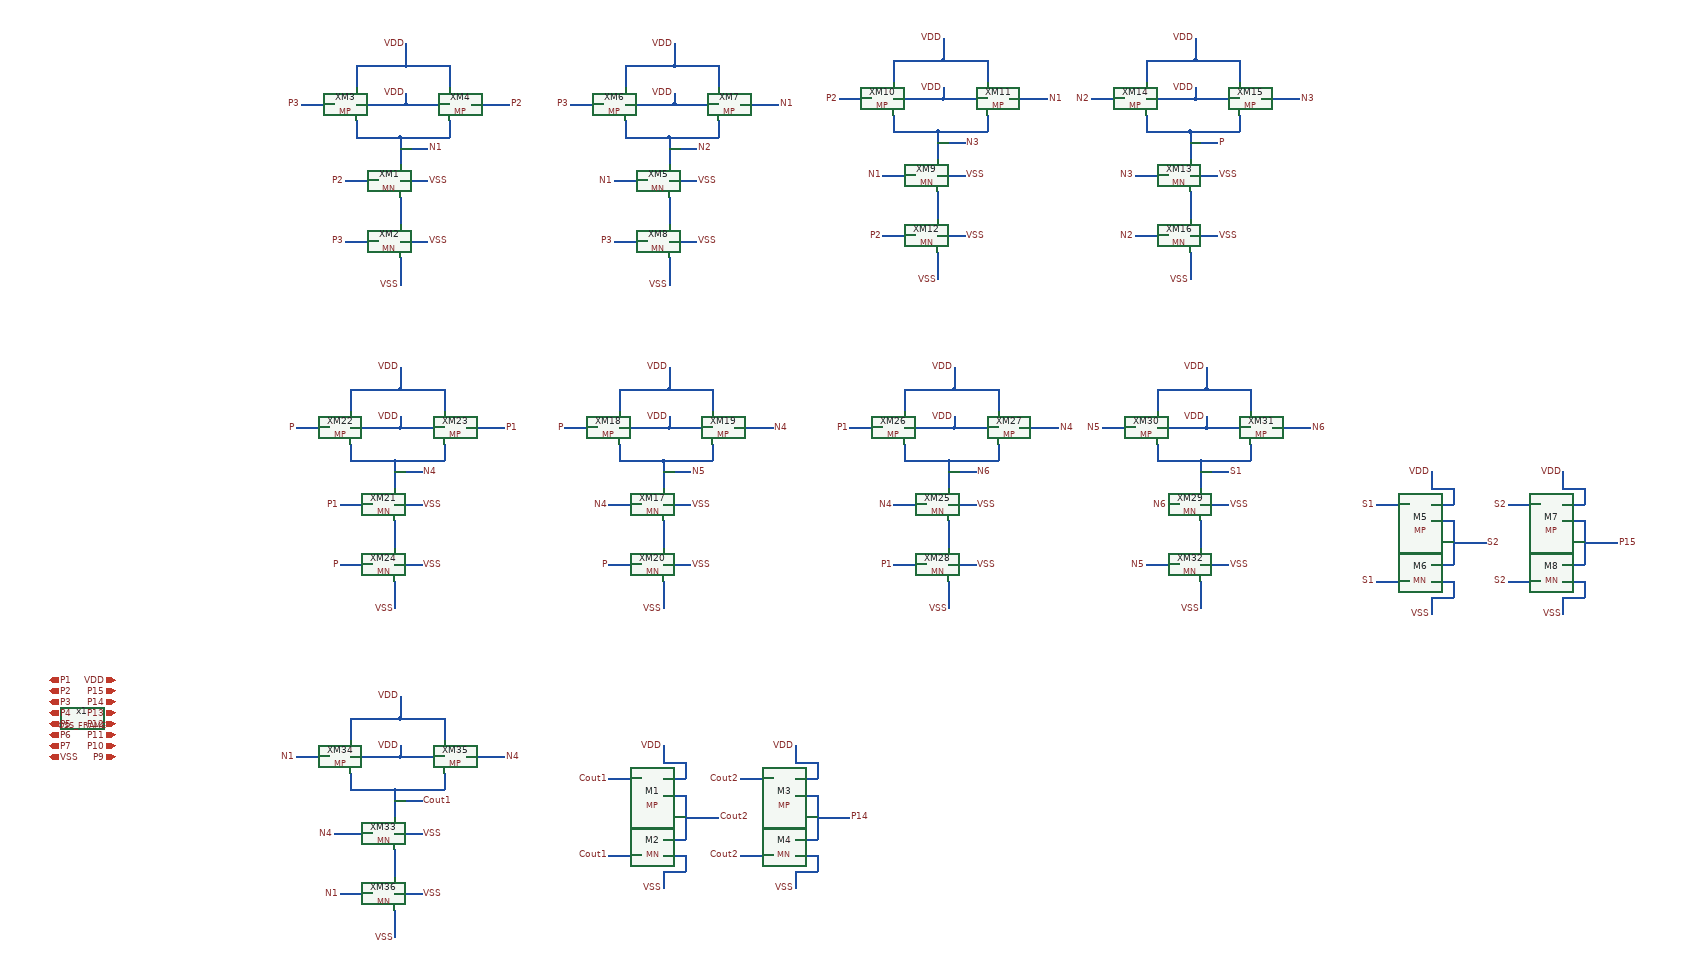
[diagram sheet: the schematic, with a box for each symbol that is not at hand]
v {xschem version=3.4.8RC file_version=1.3}
G {}
K {}
V {}
S {}
F {}
E {}
N 830 -1630 900 -1630 {lab=P2}
N 520 -1630 580 -1630 {lab=P3}
N 710 -1740 710 -1700 {lab=VDD}
N 710 -1700 790 -1700 {lab=VDD}
N 790 -1700 790 -1660 {lab=VDD}
N 620 -1700 710 -1700 {lab=VDD}
N 620 -1700 620 -1660 {lab=VDD}
N 790 -1600 790 -1570 {lab=N1}
N 700 -1570 790 -1570 {lab=N1}
N 700 -1570 700 -1520 {lab=N1}
N 620 -1600 620 -1570 {lab=N1}
N 620 -1570 700 -1570 {lab=N1}
N 700 -1550 750 -1550 {lab=N1}
N 600 -1490 660 -1490 {lab=P2}
N 600 -1380 660 -1380 {lab=P3}
N 700 -1460 700 -1440 {lab=#net1}
N 700 -1440 700 -1410 {lab=#net1}
N 700 -1350 700 -1300 {lab=VSS}
N 700 -1380 750 -1380 {lab=VSS}
N 700 -1490 750 -1490 {lab=VSS}
N 620 -1630 710 -1630 {lab=VDD}
N 710 -1650 710 -1630 {lab=VDD}
N 710 -1630 790 -1630 {lab=VDD}
N 1320 -1630 1390 -1630 {lab=N1}
N 1010 -1630 1070 -1630 {lab=P3}
N 1200 -1740 1200 -1700 {lab=VDD}
N 1200 -1700 1280 -1700 {lab=VDD}
N 1280 -1700 1280 -1660 {lab=VDD}
N 1110 -1700 1200 -1700 {lab=VDD}
N 1110 -1700 1110 -1660 {lab=VDD}
N 1280 -1600 1280 -1570 {lab=N2}
N 1190 -1570 1280 -1570 {lab=N2}
N 1190 -1570 1190 -1520 {lab=N2}
N 1110 -1600 1110 -1570 {lab=N2}
N 1110 -1570 1190 -1570 {lab=N2}
N 1190 -1550 1240 -1550 {lab=N2}
N 1090 -1490 1150 -1490 {lab=N1}
N 1090 -1380 1150 -1380 {lab=P3}
N 1190 -1460 1190 -1440 {lab=#net2}
N 1190 -1440 1190 -1410 {lab=#net2}
N 1190 -1350 1190 -1300 {lab=VSS}
N 1190 -1380 1240 -1380 {lab=VSS}
N 1190 -1490 1240 -1490 {lab=VSS}
N 1110 -1630 1200 -1630 {lab=VDD}
N 1200 -1650 1200 -1630 {lab=VDD}
N 1200 -1630 1280 -1630 {lab=VDD}
N 1810 -1640 1880 -1640 {lab=N1}
N 1500 -1640 1560 -1640 {lab=P2}
N 1690 -1750 1690 -1710 {lab=VDD}
N 1690 -1710 1770 -1710 {lab=VDD}
N 1770 -1710 1770 -1670 {lab=VDD}
N 1600 -1710 1690 -1710 {lab=VDD}
N 1600 -1710 1600 -1670 {lab=VDD}
N 1770 -1610 1770 -1580 {lab=N3}
N 1680 -1580 1770 -1580 {lab=N3}
N 1680 -1580 1680 -1530 {lab=N3}
N 1600 -1610 1600 -1580 {lab=N3}
N 1600 -1580 1680 -1580 {lab=N3}
N 1680 -1560 1730 -1560 {lab=N3}
N 1580 -1500 1640 -1500 {lab=N1}
N 1580 -1390 1640 -1390 {lab=P2}
N 1680 -1470 1680 -1450 {lab=#net3}
N 1680 -1450 1680 -1420 {lab=#net3}
N 1680 -1360 1680 -1310 {lab=VSS}
N 1680 -1390 1730 -1390 {lab=VSS}
N 1680 -1500 1730 -1500 {lab=VSS}
N 1600 -1640 1690 -1640 {lab=VDD}
N 1690 -1660 1690 -1640 {lab=VDD}
N 1690 -1640 1770 -1640 {lab=VDD}
N 2270 -1640 2340 -1640 {lab=N3}
N 1960 -1640 2020 -1640 {lab=N2}
N 2150 -1750 2150 -1710 {lab=VDD}
N 2150 -1710 2230 -1710 {lab=VDD}
N 2230 -1710 2230 -1670 {lab=VDD}
N 2060 -1710 2150 -1710 {lab=VDD}
N 2060 -1710 2060 -1670 {lab=VDD}
N 2230 -1610 2230 -1580 {lab=P}
N 2140 -1580 2230 -1580 {lab=P}
N 2140 -1580 2140 -1530 {lab=P}
N 2060 -1610 2060 -1580 {lab=P}
N 2060 -1580 2140 -1580 {lab=P}
N 2140 -1560 2190 -1560 {lab=P}
N 2040 -1500 2100 -1500 {lab=N3}
N 2040 -1390 2100 -1390 {lab=N2}
N 2140 -1470 2140 -1450 {lab=#net4}
N 2140 -1450 2140 -1420 {lab=#net4}
N 2140 -1360 2140 -1310 {lab=VSS}
N 2140 -1390 2190 -1390 {lab=VSS}
N 2140 -1500 2190 -1500 {lab=VSS}
N 2060 -1640 2150 -1640 {lab=VDD}
N 2150 -1660 2150 -1640 {lab=VDD}
N 2150 -1640 2230 -1640 {lab=VDD}
N 1310 -1040 1380 -1040 {lab=N4}
N 1000 -1040 1060 -1040 {lab=P}
N 1190 -1150 1190 -1110 {lab=VDD}
N 1190 -1110 1270 -1110 {lab=VDD}
N 1270 -1110 1270 -1070 {lab=VDD}
N 1100 -1110 1190 -1110 {lab=VDD}
N 1100 -1110 1100 -1070 {lab=VDD}
N 1270 -1010 1270 -980 {lab=N5}
N 1180 -980 1270 -980 {lab=N5}
N 1180 -980 1180 -930 {lab=N5}
N 1100 -1010 1100 -980 {lab=N5}
N 1100 -980 1180 -980 {lab=N5}
N 1180 -960 1230 -960 {lab=N5}
N 1080 -900 1140 -900 {lab=N4}
N 1080 -790 1140 -790 {lab=P}
N 1180 -870 1180 -850 {lab=#net5}
N 1180 -850 1180 -820 {lab=#net5}
N 1180 -760 1180 -710 {lab=VSS}
N 1180 -790 1230 -790 {lab=VSS}
N 1180 -900 1230 -900 {lab=VSS}
N 1100 -1040 1190 -1040 {lab=VDD}
N 1190 -1060 1190 -1040 {lab=VDD}
N 1190 -1040 1270 -1040 {lab=VDD}
N 820 -1040 890 -1040 {lab=P1}
N 510 -1040 570 -1040 {lab=P}
N 700 -1150 700 -1110 {lab=VDD}
N 700 -1110 780 -1110 {lab=VDD}
N 780 -1110 780 -1070 {lab=VDD}
N 610 -1110 700 -1110 {lab=VDD}
N 610 -1110 610 -1070 {lab=VDD}
N 780 -1010 780 -980 {lab=N4}
N 690 -980 780 -980 {lab=N4}
N 690 -980 690 -930 {lab=N4}
N 610 -1010 610 -980 {lab=N4}
N 610 -980 690 -980 {lab=N4}
N 690 -960 740 -960 {lab=N4}
N 590 -900 650 -900 {lab=P1}
N 590 -790 650 -790 {lab=P}
N 690 -870 690 -850 {lab=#net6}
N 690 -850 690 -820 {lab=#net6}
N 690 -760 690 -710 {lab=VSS}
N 690 -790 740 -790 {lab=VSS}
N 690 -900 740 -900 {lab=VSS}
N 610 -1040 700 -1040 {lab=VDD}
N 700 -1060 700 -1040 {lab=VDD}
N 700 -1040 780 -1040 {lab=VDD}
N 1830 -1040 1900 -1040 {lab=N4}
N 1520 -1040 1580 -1040 {lab=P1}
N 1710 -1150 1710 -1110 {lab=VDD}
N 1710 -1110 1790 -1110 {lab=VDD}
N 1790 -1110 1790 -1070 {lab=VDD}
N 1620 -1110 1710 -1110 {lab=VDD}
N 1620 -1110 1620 -1070 {lab=VDD}
N 1790 -1010 1790 -980 {lab=N6}
N 1700 -980 1790 -980 {lab=N6}
N 1700 -980 1700 -930 {lab=N6}
N 1620 -1010 1620 -980 {lab=N6}
N 1620 -980 1700 -980 {lab=N6}
N 1700 -960 1750 -960 {lab=N6}
N 1600 -900 1660 -900 {lab=N4}
N 1600 -790 1660 -790 {lab=P1}
N 1700 -870 1700 -850 {lab=#net7}
N 1700 -850 1700 -820 {lab=#net7}
N 1700 -760 1700 -710 {lab=VSS}
N 1700 -790 1750 -790 {lab=VSS}
N 1700 -900 1750 -900 {lab=VSS}
N 1620 -1040 1710 -1040 {lab=VDD}
N 1710 -1060 1710 -1040 {lab=VDD}
N 1710 -1040 1790 -1040 {lab=VDD}
N 2290 -1040 2360 -1040 {lab=N6}
N 1980 -1040 2040 -1040 {lab=N5}
N 2170 -1150 2170 -1110 {lab=VDD}
N 2170 -1110 2250 -1110 {lab=VDD}
N 2250 -1110 2250 -1070 {lab=VDD}
N 2080 -1110 2170 -1110 {lab=VDD}
N 2080 -1110 2080 -1070 {lab=VDD}
N 2250 -1010 2250 -980 {lab=S1}
N 2160 -980 2250 -980 {lab=S1}
N 2160 -980 2160 -930 {lab=S1}
N 2080 -1010 2080 -980 {lab=S1}
N 2080 -980 2160 -980 {lab=S1}
N 2160 -960 2210 -960 {lab=S1}
N 2060 -790 2120 -790 {lab=N5}
N 2160 -870 2160 -850 {lab=#net8}
N 2160 -850 2160 -820 {lab=#net8}
N 2160 -760 2160 -710 {lab=VSS}
N 2160 -790 2210 -790 {lab=VSS}
N 2160 -900 2210 -900 {lab=VSS}
N 2080 -1040 2170 -1040 {lab=VDD}
N 2170 -1060 2170 -1040 {lab=VDD}
N 2170 -1040 2250 -1040 {lab=VDD}
N 820 -440 890 -440 {lab=N4}
N 510 -440 570 -440 {lab=N1}
N 700 -550 700 -510 {lab=VDD}
N 700 -510 780 -510 {lab=VDD}
N 780 -510 780 -470 {lab=VDD}
N 610 -510 700 -510 {lab=VDD}
N 610 -510 610 -470 {lab=VDD}
N 780 -410 780 -380 {lab=Cout}
N 690 -380 780 -380 {lab=Cout}
N 690 -380 690 -330 {lab=Cout}
N 610 -410 610 -380 {lab=Cout}
N 610 -380 690 -380 {lab=Cout}
N 690 -360 740 -360 {lab=Cout}
N 590 -190 650 -190 {lab=N1}
N 690 -270 690 -250 {lab=#net9}
N 690 -250 690 -220 {lab=#net9}
N 690 -160 690 -110 {lab=VSS}
N 690 -190 740 -190 {lab=VSS}
N 690 -300 740 -300 {lab=VSS}
N 610 -440 700 -440 {lab=VDD}
N 700 -460 700 -440 {lab=VDD}
N 700 -440 780 -440 {lab=VDD}
N 580 -300 650 -300 {lab=N4}
N 2100 -900 2120 -900 {lab=N6}
N 1080 -400 1140 -400 {lab=Cout1}
N 1080 -260 1140 -260 {lab=Cout1}
N 1180 -370 1220 -370 {lab=Cout2}
N 1180 -290 1220 -290 {lab=Cout2}
N 1220 -370 1220 -290 {lab=Cout2}
N 1220 -330 1280 -330 {lab=Cout2}
N 1180 -460 1180 -430 {lab=VDD}
N 1180 -430 1220 -430 {lab=VDD}
N 1220 -430 1220 -400 {lab=VDD}
N 1180 -400 1220 -400 {lab=VDD}
N 1180 -230 1180 -200 {lab=VSS}
N 1180 -260 1220 -260 {lab=VSS}
N 1220 -260 1220 -230 {lab=VSS}
N 1180 -230 1220 -230 {lab=VSS}
N 1320 -400 1380 -400 {lab=Cout2}
N 1320 -260 1380 -260 {lab=Cout2}
N 1420 -370 1460 -370 {lab=P14}
N 1420 -290 1460 -290 {lab=P14}
N 1460 -370 1460 -290 {lab=P14}
N 1460 -330 1520 -330 {lab=P14}
N 1420 -460 1420 -430 {lab=VDD}
N 1420 -430 1460 -430 {lab=VDD}
N 1460 -430 1460 -400 {lab=VDD}
N 1420 -400 1460 -400 {lab=VDD}
N 1420 -230 1420 -200 {lab=VSS}
N 1420 -260 1460 -260 {lab=VSS}
N 1460 -260 1460 -230 {lab=VSS}
N 1420 -230 1460 -230 {lab=VSS}
N 2480 -900 2540 -900 {lab=S1}
N 2480 -760 2540 -760 {lab=S1}
N 2580 -870 2620 -870 {lab=S2}
N 2580 -790 2620 -790 {lab=S2}
N 2620 -870 2620 -790 {lab=S2}
N 2620 -830 2680 -830 {lab=S2}
N 2580 -960 2580 -930 {lab=VDD}
N 2580 -930 2620 -930 {lab=VDD}
N 2620 -930 2620 -900 {lab=VDD}
N 2580 -900 2620 -900 {lab=VDD}
N 2580 -730 2580 -700 {lab=VSS}
N 2580 -760 2620 -760 {lab=VSS}
N 2620 -760 2620 -730 {lab=VSS}
N 2580 -730 2620 -730 {lab=VSS}
N 2720 -900 2780 -900 {lab=S2}
N 2720 -760 2780 -760 {lab=S2}
N 2820 -870 2860 -870 {lab=P15}
N 2820 -790 2860 -790 {lab=P15}
N 2860 -870 2860 -790 {lab=P15}
N 2860 -830 2920 -830 {lab=P15}
N 2820 -960 2820 -930 {lab=VDD}
N 2820 -930 2860 -930 {lab=VDD}
N 2860 -930 2860 -900 {lab=VDD}
N 2820 -900 2860 -900 {lab=VDD}
N 2820 -730 2820 -700 {lab=VSS}
N 2820 -760 2860 -760 {lab=VSS}
N 2860 -760 2860 -730 {lab=VSS}
N 2820 -730 2860 -730 {lab=VSS}
C {devices/title.sym} 0 0 0 0 {name=l1 author="jun1okamura"}
C {OSS_FRAME.sym} 120 -510 0 0 {name=x1}
C {devices/iopin.sym} 60 -580 0 1 {name=p1 lab=P1}
C {devices/iopin.sym} 60 -560 0 1 {name=p2 lab=P2}
C {devices/iopin.sym} 60 -540 0 1 {name=p3 lab=P3}
C {devices/iopin.sym} 60 -520 0 1 {name=p4 lab=P4
}
C {devices/iopin.sym} 60 -500 0 1 {name=p5 lab=P5}
C {devices/iopin.sym} 60 -480 0 1 {name=p6 lab=P6}
C {devices/iopin.sym} 60 -460 0 1 {name=p7 lab=P7}
C {devices/iopin.sym} 60 -440 0 1 {name=p8 lab=VSS}
C {devices/iopin.sym} 180 -580 0 0 {name=p9 lab=VDD}
C {devices/iopin.sym} 180 -560 0 0 {name=p10 lab=P15}
C {devices/iopin.sym} 180 -540 0 0 {name=p11 lab=P14}
C {devices/iopin.sym} 180 -520 0 0 {name=p12 lab=P13
}
C {devices/iopin.sym} 180 -500 0 0 {name=p13 lab=P12}
C {devices/iopin.sym} 180 -480 0 0 {name=p14 lab=P11}
C {devices/iopin.sym} 180 -460 0 0 {name=p15 lab=P10}
C {devices/iopin.sym} 180 -440 0 0 {name=p16 lab=P9}
C {devices/lab_pin.sym} 520 -1630 0 0 {name=p17 sig_type=std_logic lab=P3}
C {devices/lab_pin.sym} 750 -1550 0 1 {name=p18 sig_type=std_logic lab=N1}
C {devices/lab_pin.sym} 900 -1630 2 0 {name=p19 sig_type=std_logic lab=P2}
C {TR-1umLIB/MN.sym} 660 -1490 0 0 {name=XM1
model=NMOS
w=3.4u
l=1u
m=1
spiceprefix=X
as=0
ad=0
ps=0
pd=0
nrd=0
nrs=0}
C {TR-1umLIB/MP.sym} 580 -1630 0 0 {name=XM3
model=PMOS
w=3.4u
l=1u
m=1
spiceprefix=X
as=0
ad=0
ps=0
pd=0
nrd=0
nrs=0}
C {TR-1umLIB/MP.sym} 830 -1630 0 1 {name=XM4
model=PMOS
w=3.4u
l=1u
m=1
spiceprefix=X
as=0
ad=0
ps=0
pd=0
nrd=0
nrs=0}
C {TR-1umLIB/MN.sym} 660 -1380 0 0 {name=XM2
model=NMOS
w=3.4u
l=1u
m=1
spiceprefix=X
as=0
ad=0
ps=0
pd=0
nrd=0
nrs=0}
C {devices/lab_pin.sym} 600 -1490 0 0 {name=p20 sig_type=std_logic lab=P2}
C {devices/lab_pin.sym} 600 -1380 0 0 {name=p21 sig_type=std_logic lab=P3}
C {devices/lab_pin.sym} 1010 -1630 0 0 {name=p22 sig_type=std_logic lab=P3}
C {devices/lab_pin.sym} 1240 -1550 0 1 {name=p23 sig_type=std_logic lab=N2}
C {devices/lab_pin.sym} 1390 -1630 2 0 {name=p24 sig_type=std_logic lab=N1}
C {TR-1umLIB/MN.sym} 1150 -1490 0 0 {name=XM5
model=NMOS
w=3.4u
l=1u
m=1
spiceprefix=X
as=0
ad=0
ps=0
pd=0
nrd=0
nrs=0}
C {TR-1umLIB/MP.sym} 1070 -1630 0 0 {name=XM6
model=PMOS
w=3.4u
l=1u
m=1
spiceprefix=X
as=0
ad=0
ps=0
pd=0
nrd=0
nrs=0}
C {TR-1umLIB/MP.sym} 1320 -1630 0 1 {name=XM7
model=PMOS
w=3.4u
l=1u
m=1
spiceprefix=X
as=0
ad=0
ps=0
pd=0
nrd=0
nrs=0}
C {TR-1umLIB/MN.sym} 1150 -1380 0 0 {name=XM8
model=NMOS
w=3.4u
l=1u
m=1
spiceprefix=X
as=0
ad=0
ps=0
pd=0
nrd=0
nrs=0}
C {devices/lab_pin.sym} 1090 -1490 0 0 {name=p25 sig_type=std_logic lab=N1}
C {devices/lab_pin.sym} 1090 -1380 0 0 {name=p26 sig_type=std_logic lab=P3}
C {devices/lab_pin.sym} 1500 -1640 0 0 {name=p27 sig_type=std_logic lab=P2}
C {devices/lab_pin.sym} 1730 -1560 0 1 {name=p28 sig_type=std_logic lab=N3}
C {devices/lab_pin.sym} 1880 -1640 2 0 {name=p29 sig_type=std_logic lab=N1}
C {TR-1umLIB/MN.sym} 1640 -1500 0 0 {name=XM9
model=NMOS
w=3.4u
l=1u
m=1
spiceprefix=X
as=0
ad=0
ps=0
pd=0
nrd=0
nrs=0}
C {TR-1umLIB/MP.sym} 1560 -1640 0 0 {name=XM10
model=PMOS
w=3.4u
l=1u
m=1
spiceprefix=X
as=0
ad=0
ps=0
pd=0
nrd=0
nrs=0}
C {TR-1umLIB/MP.sym} 1810 -1640 0 1 {name=XM11
model=PMOS
w=3.4u
l=1u
m=1
spiceprefix=X
as=0
ad=0
ps=0
pd=0
nrd=0
nrs=0}
C {TR-1umLIB/MN.sym} 1640 -1390 0 0 {name=XM12
model=NMOS
w=3.4u
l=1u
m=1
spiceprefix=X
as=0
ad=0
ps=0
pd=0
nrd=0
nrs=0}
C {devices/lab_pin.sym} 1580 -1500 0 0 {name=p30 sig_type=std_logic lab=N1}
C {devices/lab_pin.sym} 1580 -1390 0 0 {name=p31 sig_type=std_logic lab=P2}
C {devices/lab_pin.sym} 1960 -1640 0 0 {name=p32 sig_type=std_logic lab=N2
}
C {devices/lab_pin.sym} 2190 -1560 0 1 {name=p33 sig_type=std_logic lab=P}
C {devices/lab_pin.sym} 2340 -1640 2 0 {name=p34 sig_type=std_logic lab=N3}
C {TR-1umLIB/MN.sym} 2100 -1500 0 0 {name=XM13
model=NMOS
w=3.4u
l=1u
m=1
spiceprefix=X
as=0
ad=0
ps=0
pd=0
nrd=0
nrs=0}
C {TR-1umLIB/MP.sym} 2020 -1640 0 0 {name=XM14
model=PMOS
w=3.4u
l=1u
m=1
spiceprefix=X
as=0
ad=0
ps=0
pd=0
nrd=0
nrs=0}
C {TR-1umLIB/MP.sym} 2270 -1640 0 1 {name=XM15
model=PMOS
w=3.4u
l=1u
m=1
spiceprefix=X
as=0
ad=0
ps=0
pd=0
nrd=0
nrs=0}
C {TR-1umLIB/MN.sym} 2100 -1390 0 0 {name=XM16
model=NMOS
w=3.4u
l=1u
m=1
spiceprefix=X
as=0
ad=0
ps=0
pd=0
nrd=0
nrs=0}
C {devices/lab_pin.sym} 2040 -1500 0 0 {name=p35 sig_type=std_logic lab=N3}
C {devices/lab_pin.sym} 2040 -1390 0 0 {name=p36 sig_type=std_logic lab=N2}
C {devices/lab_pin.sym} 1000 -1040 0 0 {name=p37 sig_type=std_logic lab=P}
C {devices/lab_pin.sym} 1230 -960 0 1 {name=p38 sig_type=std_logic lab=N5}
C {devices/lab_pin.sym} 1380 -1040 2 0 {name=p39 sig_type=std_logic lab=N4}
C {TR-1umLIB/MN.sym} 1140 -900 0 0 {name=XM17
model=NMOS
w=3.4u
l=1u
m=1
spiceprefix=X
as=0
ad=0
ps=0
pd=0
nrd=0
nrs=0}
C {TR-1umLIB/MP.sym} 1060 -1040 0 0 {name=XM18
model=PMOS
w=3.4u
l=1u
m=1
spiceprefix=X
as=0
ad=0
ps=0
pd=0
nrd=0
nrs=0}
C {TR-1umLIB/MP.sym} 1310 -1040 0 1 {name=XM19
model=PMOS
w=3.4u
l=1u
m=1
spiceprefix=X
as=0
ad=0
ps=0
pd=0
nrd=0
nrs=0}
C {TR-1umLIB/MN.sym} 1140 -790 0 0 {name=XM20
model=NMOS
w=3.4u
l=1u
m=1
spiceprefix=X
as=0
ad=0
ps=0
pd=0
nrd=0
nrs=0}
C {devices/lab_pin.sym} 1080 -790 0 0 {name=p40 sig_type=std_logic lab=P}
C {devices/lab_pin.sym} 1080 -900 0 0 {name=p41 sig_type=std_logic lab=N4}
C {devices/lab_pin.sym} 510 -1040 0 0 {name=p42 sig_type=std_logic lab=P}
C {devices/lab_pin.sym} 740 -960 0 1 {name=p43 sig_type=std_logic lab=N4}
C {devices/lab_pin.sym} 890 -1040 2 0 {name=p44 sig_type=std_logic lab=P1}
C {TR-1umLIB/MN.sym} 650 -900 0 0 {name=XM21
model=NMOS
w=3.4u
l=1u
m=1
spiceprefix=X
as=0
ad=0
ps=0
pd=0
nrd=0
nrs=0}
C {TR-1umLIB/MP.sym} 570 -1040 0 0 {name=XM22
model=PMOS
w=3.4u
l=1u
m=1
spiceprefix=X
as=0
ad=0
ps=0
pd=0
nrd=0
nrs=0}
C {TR-1umLIB/MP.sym} 820 -1040 0 1 {name=XM23
model=PMOS
w=3.4u
l=1u
m=1
spiceprefix=X
as=0
ad=0
ps=0
pd=0
nrd=0
nrs=0}
C {TR-1umLIB/MN.sym} 650 -790 0 0 {name=XM24
model=NMOS
w=3.4u
l=1u
m=1
spiceprefix=X
as=0
ad=0
ps=0
pd=0
nrd=0
nrs=0}
C {devices/lab_pin.sym} 590 -900 0 0 {name=p45 sig_type=std_logic lab=P1}
C {devices/lab_pin.sym} 590 -790 0 0 {name=p46 sig_type=std_logic lab=P}
C {devices/lab_pin.sym} 1520 -1040 0 0 {name=p47 sig_type=std_logic lab=P1}
C {devices/lab_pin.sym} 1750 -960 0 1 {name=p48 sig_type=std_logic lab=N6
}
C {devices/lab_pin.sym} 1900 -1040 2 0 {name=p49 sig_type=std_logic lab=N4}
C {TR-1umLIB/MN.sym} 1660 -900 0 0 {name=XM25
model=NMOS
w=3.4u
l=1u
m=1
spiceprefix=X
as=0
ad=0
ps=0
pd=0
nrd=0
nrs=0}
C {TR-1umLIB/MP.sym} 1580 -1040 0 0 {name=XM26
model=PMOS
w=3.4u
l=1u
m=1
spiceprefix=X
as=0
ad=0
ps=0
pd=0
nrd=0
nrs=0}
C {TR-1umLIB/MP.sym} 1830 -1040 0 1 {name=XM27
model=PMOS
w=3.4u
l=1u
m=1
spiceprefix=X
as=0
ad=0
ps=0
pd=0
nrd=0
nrs=0}
C {TR-1umLIB/MN.sym} 1660 -790 0 0 {name=XM28
model=NMOS
w=3.4u
l=1u
m=1
spiceprefix=X
as=0
ad=0
ps=0
pd=0
nrd=0
nrs=0}
C {devices/lab_pin.sym} 1600 -790 0 0 {name=p50 sig_type=std_logic lab=P1}
C {devices/lab_pin.sym} 1600 -900 0 0 {name=p51 sig_type=std_logic lab=N4}
C {devices/lab_pin.sym} 1980 -1040 0 0 {name=p52 sig_type=std_logic lab=N5
}
C {devices/lab_pin.sym} 2210 -960 0 1 {name=p53 sig_type=std_logic lab=S1}
C {devices/lab_pin.sym} 2360 -1040 2 0 {name=p54 sig_type=std_logic lab=N6}
C {TR-1umLIB/MN.sym} 2120 -900 0 0 {name=XM29
model=NMOS
w=3.4u
l=1u
m=1
spiceprefix=X
as=0
ad=0
ps=0
pd=0
nrd=0
nrs=0}
C {TR-1umLIB/MP.sym} 2040 -1040 0 0 {name=XM30
model=PMOS
w=3.4u
l=1u
m=1
spiceprefix=X
as=0
ad=0
ps=0
pd=0
nrd=0
nrs=0}
C {TR-1umLIB/MP.sym} 2290 -1040 0 1 {name=XM31
model=PMOS
w=3.4u
l=1u
m=1
spiceprefix=X
as=0
ad=0
ps=0
pd=0
nrd=0
nrs=0}
C {TR-1umLIB/MN.sym} 2120 -790 0 0 {name=XM32
model=NMOS
w=3.4u
l=1u
m=1
spiceprefix=X
as=0
ad=0
ps=0
pd=0
nrd=0
nrs=0}
C {devices/lab_pin.sym} 2060 -790 0 0 {name=p55 sig_type=std_logic lab=N5}
C {devices/lab_pin.sym} 2100 -900 0 0 {name=p56 sig_type=std_logic lab=N6}
C {devices/lab_pin.sym} 510 -440 0 0 {name=p57 sig_type=std_logic lab=N1
}
C {devices/lab_pin.sym} 740 -360 0 1 {name=p58 sig_type=std_logic lab=Cout1}
C {devices/lab_pin.sym} 890 -440 2 0 {name=p59 sig_type=std_logic lab=N4}
C {TR-1umLIB/MN.sym} 650 -300 0 0 {name=XM33
model=NMOS
w=3.4u
l=1u
m=1
spiceprefix=X
as=0
ad=0
ps=0
pd=0
nrd=0
nrs=0}
C {TR-1umLIB/MP.sym} 570 -440 0 0 {name=XM34
model=PMOS
w=3.4u
l=1u
m=1
spiceprefix=X
as=0
ad=0
ps=0
pd=0
nrd=0
nrs=0}
C {TR-1umLIB/MP.sym} 820 -440 0 1 {name=XM35
model=PMOS
w=3.4u
l=1u
m=1
spiceprefix=X
as=0
ad=0
ps=0
pd=0
nrd=0
nrs=0}
C {TR-1umLIB/MN.sym} 650 -190 0 0 {name=XM36
model=NMOS
w=3.4u
l=1u
m=1
spiceprefix=X
as=0
ad=0
ps=0
pd=0
nrd=0
nrs=0}
C {devices/lab_pin.sym} 590 -190 0 0 {name=p60 sig_type=std_logic lab=N1}
C {devices/lab_pin.sym} 580 -300 0 0 {name=p61 sig_type=std_logic lab=N4}
C {devices/lab_pin.sym} 700 -550 0 0 {name=p62 sig_type=std_logic lab=VDD
}
C {devices/lab_pin.sym} 700 -1150 0 0 {name=p63 sig_type=std_logic lab=VDD
}
C {devices/lab_pin.sym} 710 -1740 0 0 {name=p64 sig_type=std_logic lab=VDD
}
C {devices/lab_pin.sym} 1200 -1740 0 0 {name=p65 sig_type=std_logic lab=VDD
}
C {devices/lab_pin.sym} 1190 -1150 0 0 {name=p66 sig_type=std_logic lab=VDD
}
C {devices/lab_pin.sym} 1710 -1150 0 0 {name=p67 sig_type=std_logic lab=VDD
}
C {devices/lab_pin.sym} 1690 -1750 0 0 {name=p68 sig_type=std_logic lab=VDD
}
C {devices/lab_pin.sym} 2150 -1750 0 0 {name=p69 sig_type=std_logic lab=VDD
}
C {devices/lab_pin.sym} 2170 -1150 0 0 {name=p70 sig_type=std_logic lab=VDD
}
C {devices/lab_pin.sym} 710 -1650 0 0 {name=p71 sig_type=std_logic lab=VDD
}
C {devices/lab_pin.sym} 1200 -1650 0 0 {name=p72 sig_type=std_logic lab=VDD
}
C {devices/lab_pin.sym} 1690 -1660 0 0 {name=p73 sig_type=std_logic lab=VDD
}
C {devices/lab_pin.sym} 2150 -1660 0 0 {name=p74 sig_type=std_logic lab=VDD
}
C {devices/lab_pin.sym} 2170 -1060 0 0 {name=p75 sig_type=std_logic lab=VDD
}
C {devices/lab_pin.sym} 1710 -1060 0 0 {name=p76 sig_type=std_logic lab=VDD
}
C {devices/lab_pin.sym} 1190 -1060 0 0 {name=p77 sig_type=std_logic lab=VDD
}
C {devices/lab_pin.sym} 700 -1060 0 0 {name=p78 sig_type=std_logic lab=VDD
}
C {devices/lab_pin.sym} 700 -460 0 0 {name=p79 sig_type=std_logic lab=VDD
}
C {devices/lab_pin.sym} 690 -110 0 0 {name=p80 sig_type=std_logic lab=VSS
}
C {devices/lab_pin.sym} 740 -190 2 0 {name=p81 sig_type=std_logic lab=VSS
}
C {devices/lab_pin.sym} 740 -300 2 0 {name=p82 sig_type=std_logic lab=VSS
}
C {devices/lab_pin.sym} 740 -790 2 0 {name=p83 sig_type=std_logic lab=VSS
}
C {devices/lab_pin.sym} 740 -900 2 0 {name=p84 sig_type=std_logic lab=VSS
}
C {devices/lab_pin.sym} 750 -1380 2 0 {name=p85 sig_type=std_logic lab=VSS
}
C {devices/lab_pin.sym} 750 -1490 2 0 {name=p86 sig_type=std_logic lab=VSS
}
C {devices/lab_pin.sym} 1240 -1380 2 0 {name=p87 sig_type=std_logic lab=VSS
}
C {devices/lab_pin.sym} 1240 -1490 2 0 {name=p88 sig_type=std_logic lab=VSS
}
C {devices/lab_pin.sym} 1730 -1390 2 0 {name=p89 sig_type=std_logic lab=VSS
}
C {devices/lab_pin.sym} 1730 -1500 2 0 {name=p90 sig_type=std_logic lab=VSS
}
C {devices/lab_pin.sym} 2190 -1390 2 0 {name=p91 sig_type=std_logic lab=VSS
}
C {devices/lab_pin.sym} 2190 -1500 2 0 {name=p92 sig_type=std_logic lab=VSS
}
C {devices/lab_pin.sym} 2210 -790 2 0 {name=p93 sig_type=std_logic lab=VSS
}
C {devices/lab_pin.sym} 2210 -900 2 0 {name=p94 sig_type=std_logic lab=VSS
}
C {devices/lab_pin.sym} 1750 -790 2 0 {name=p95 sig_type=std_logic lab=VSS
}
C {devices/lab_pin.sym} 1750 -900 2 0 {name=p96 sig_type=std_logic lab=VSS
}
C {devices/lab_pin.sym} 1230 -790 2 0 {name=p97 sig_type=std_logic lab=VSS
}
C {devices/lab_pin.sym} 1230 -900 2 0 {name=p98 sig_type=std_logic lab=VSS
}
C {devices/lab_pin.sym} 690 -710 0 0 {name=p99 sig_type=std_logic lab=VSS
}
C {devices/lab_pin.sym} 700 -1300 0 0 {name=p100 sig_type=std_logic lab=VSS
}
C {devices/lab_pin.sym} 1190 -1300 0 0 {name=p101 sig_type=std_logic lab=VSS
}
C {devices/lab_pin.sym} 1680 -1310 0 0 {name=p102 sig_type=std_logic lab=VSS
}
C {devices/lab_pin.sym} 1180 -710 0 0 {name=p103 sig_type=std_logic lab=VSS
}
C {devices/lab_pin.sym} 1700 -710 0 0 {name=p104 sig_type=std_logic lab=VSS
}
C {devices/lab_pin.sym} 2160 -710 0 0 {name=p105 sig_type=std_logic lab=VSS
}
C {devices/lab_pin.sym} 2140 -1310 0 0 {name=p106 sig_type=std_logic lab=VSS
}
C {devices/lab_pin.sym} 1080 -400 0 0 {name=p113 sig_type=std_logic lab=Cout1}
C {devices/lab_pin.sym} 1080 -260 0 0 {name=p114 sig_type=std_logic lab=Cout1}
C {devices/lab_pin.sym} 1280 -330 2 0 {name=p115 sig_type=std_logic lab=Cout2}
C {TR-1umLIB/MP.sym} 1140 -400 0 0 {name=M1
model=PMOS
w=10u
l=1u
m=1
spiceprefix=X
as=0
ad=0
ps=0
pd=0
nrd=0
nrs=0}
C {TR-1umLIB/MN.sym} 1140 -260 0 0 {name=M2
model=NMOS
w=5u
l=1u
m=1
spiceprefix=X
as=0
ad=0
ps=0
pd=0
nrd=0
nrs=0}
C {devices/lab_pin.sym} 1320 -400 0 0 {name=p116 sig_type=std_logic lab=Cout2}
C {devices/lab_pin.sym} 1320 -260 0 0 {name=p117 sig_type=std_logic lab=Cout2}
C {devices/lab_pin.sym} 1520 -330 2 0 {name=p118 sig_type=std_logic lab=P14}
C {TR-1umLIB/MP.sym} 1380 -400 0 0 {name=M3
model=PMOS
w=20u
l=1u
m=2
spiceprefix=X
as=0
ad=0
ps=0
pd=0
nrd=0
nrs=0}
C {TR-1umLIB/MN.sym} 1380 -260 0 0 {name=M4
model=NMOS
w=10u
l=1u
m=2
spiceprefix=X
as=0
ad=0
ps=0
pd=0
nrd=0
nrs=0}
C {devices/lab_pin.sym} 1180 -460 0 0 {name=p119 sig_type=std_logic lab=VDD
}
C {devices/lab_pin.sym} 1420 -460 0 0 {name=p120 sig_type=std_logic lab=VDD
}
C {devices/lab_pin.sym} 1180 -200 0 0 {name=p121 sig_type=std_logic lab=VSS
}
C {devices/lab_pin.sym} 1420 -200 0 0 {name=p122 sig_type=std_logic lab=VSS
}
C {devices/lab_pin.sym} 2480 -900 0 0 {name=p107 sig_type=std_logic lab=S1}
C {devices/lab_pin.sym} 2480 -760 0 0 {name=p108 sig_type=std_logic lab=S1}
C {devices/lab_pin.sym} 2680 -830 2 0 {name=p109 sig_type=std_logic lab=S2}
C {TR-1umLIB/MP.sym} 2540 -900 0 0 {name=M5
model=PMOS
w=10u
l=1u
m=1
spiceprefix=X
as=0
ad=0
ps=0
pd=0
nrd=0
nrs=0}
C {TR-1umLIB/MN.sym} 2540 -760 0 0 {name=M6
model=NMOS
w=5u
l=1u
m=1
spiceprefix=X
as=0
ad=0
ps=0
pd=0
nrd=0
nrs=0}
C {devices/lab_pin.sym} 2720 -900 0 0 {name=p110 sig_type=std_logic lab=S2}
C {devices/lab_pin.sym} 2720 -760 0 0 {name=p111 sig_type=std_logic lab=S2}
C {devices/lab_pin.sym} 2920 -830 2 0 {name=p112 sig_type=std_logic lab=P15}
C {TR-1umLIB/MP.sym} 2780 -900 0 0 {name=M7
model=PMOS
w=20u
l=1u
m=2
spiceprefix=X
as=0
ad=0
ps=0
pd=0
nrd=0
nrs=0}
C {TR-1umLIB/MN.sym} 2780 -760 0 0 {name=M8
model=NMOS
w=10u
l=1u
m=2
spiceprefix=X
as=0
ad=0
ps=0
pd=0
nrd=0
nrs=0}
C {devices/lab_pin.sym} 2580 -960 0 0 {name=p123 sig_type=std_logic lab=VDD
}
C {devices/lab_pin.sym} 2820 -960 0 0 {name=p124 sig_type=std_logic lab=VDD
}
C {devices/lab_pin.sym} 2580 -700 0 0 {name=p125 sig_type=std_logic lab=VSS
}
C {devices/lab_pin.sym} 2820 -700 0 0 {name=p126 sig_type=std_logic lab=VSS
}
